###############################################################
#  Generated by:      Cadence Innovus 23.14-s088_1
#  OS:                Linux x86_64(Host ID user1-EliteMini)
#  Generated on:      Sun Jul 19 00:55:51 2026
#  Design:            Multiplier32
#  Command:           write_lef_abstract -noCutObs .outputs/Multiplier.lef
###############################################################

VERSION 5.8 ;

BUSBITCHARS "[]" ;
DIVIDERCHAR "/" ;

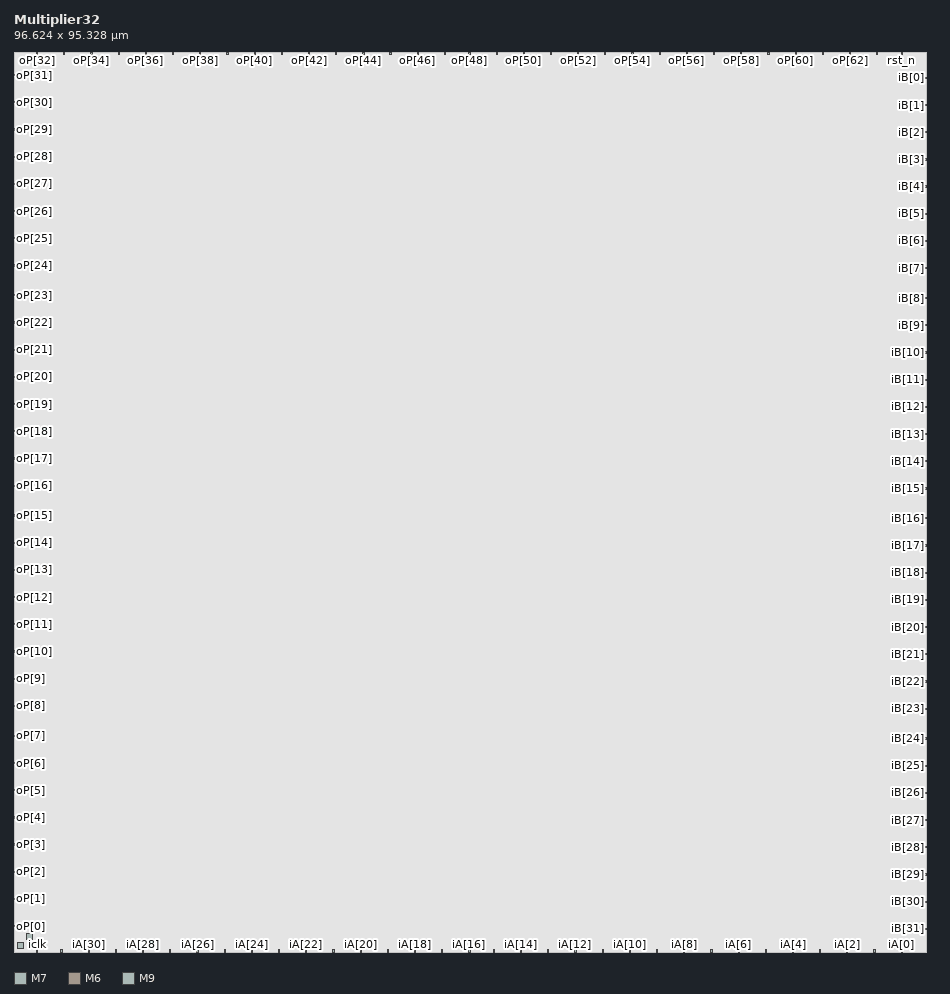
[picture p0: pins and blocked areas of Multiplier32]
MACRO Multiplier32
  CLASS BLOCK ;
  SIZE 96.624000 BY 95.328000 ;
  FOREIGN Multiplier32 0.000000 0.000000 ;
  ORIGIN 0 0 ;
  SYMMETRY X Y R90 ;
  PIN iclk
    DIRECTION INPUT ;
    USE SIGNAL ;
    PORT
      LAYER M7 ;
        RECT 2.384000 0.000000 2.512000 0.288000 ;
    END
  END iclk
  PIN rst_n
    DIRECTION INPUT ;
    USE SIGNAL ;
    PORT
      LAYER M7 ;
        RECT 93.968000 95.040000 94.096000 95.328000 ;
    END
  END rst_n
  PIN iA[31]
    DIRECTION INPUT ;
    USE SIGNAL ;
    PORT
      LAYER M7 ;
        RECT 4.976000 0.000000 5.104000 0.288000 ;
    END
  END iA[31]
  PIN iA[30]
    DIRECTION INPUT ;
    USE SIGNAL ;
    PORT
      LAYER M7 ;
        RECT 7.856000 0.000000 7.984000 0.288000 ;
    END
  END iA[30]
  PIN iA[29]
    DIRECTION INPUT ;
    USE SIGNAL ;
    PORT
      LAYER M7 ;
        RECT 10.736000 0.000000 10.864000 0.288000 ;
    END
  END iA[29]
  PIN iA[28]
    DIRECTION INPUT ;
    USE SIGNAL ;
    PORT
      LAYER M7 ;
        RECT 13.616000 0.000000 13.744000 0.288000 ;
    END
  END iA[28]
  PIN iA[27]
    DIRECTION INPUT ;
    USE SIGNAL ;
    PORT
      LAYER M7 ;
        RECT 16.496000 0.000000 16.624000 0.288000 ;
    END
  END iA[27]
  PIN iA[26]
    DIRECTION INPUT ;
    USE SIGNAL ;
    PORT
      LAYER M7 ;
        RECT 19.376000 0.000000 19.504000 0.288000 ;
    END
  END iA[26]
  PIN iA[25]
    DIRECTION INPUT ;
    USE SIGNAL ;
    PORT
      LAYER M7 ;
        RECT 22.256000 0.000000 22.384000 0.288000 ;
    END
  END iA[25]
  PIN iA[24]
    DIRECTION INPUT ;
    USE SIGNAL ;
    PORT
      LAYER M7 ;
        RECT 25.136000 0.000000 25.264000 0.288000 ;
    END
  END iA[24]
  PIN iA[23]
    DIRECTION INPUT ;
    USE SIGNAL ;
    PORT
      LAYER M7 ;
        RECT 28.016000 0.000000 28.144000 0.288000 ;
    END
  END iA[23]
  PIN iA[22]
    DIRECTION INPUT ;
    USE SIGNAL ;
    PORT
      LAYER M7 ;
        RECT 30.896000 0.000000 31.024000 0.288000 ;
    END
  END iA[22]
  PIN iA[21]
    DIRECTION INPUT ;
    USE SIGNAL ;
    PORT
      LAYER M7 ;
        RECT 33.776000 0.000000 33.904000 0.288000 ;
    END
  END iA[21]
  PIN iA[20]
    DIRECTION INPUT ;
    USE SIGNAL ;
    PORT
      LAYER M7 ;
        RECT 36.656000 0.000000 36.784000 0.288000 ;
    END
  END iA[20]
  PIN iA[19]
    DIRECTION INPUT ;
    USE SIGNAL ;
    PORT
      LAYER M7 ;
        RECT 39.536000 0.000000 39.664000 0.288000 ;
    END
  END iA[19]
  PIN iA[18]
    DIRECTION INPUT ;
    USE SIGNAL ;
    PORT
      LAYER M7 ;
        RECT 42.416000 0.000000 42.544000 0.288000 ;
    END
  END iA[18]
  PIN iA[17]
    DIRECTION INPUT ;
    USE SIGNAL ;
    PORT
      LAYER M7 ;
        RECT 45.296000 0.000000 45.424000 0.288000 ;
    END
  END iA[17]
  PIN iA[16]
    DIRECTION INPUT ;
    USE SIGNAL ;
    PORT
      LAYER M7 ;
        RECT 48.176000 0.000000 48.304000 0.288000 ;
    END
  END iA[16]
  PIN iA[15]
    DIRECTION INPUT ;
    USE SIGNAL ;
    PORT
      LAYER M7 ;
        RECT 50.768000 0.000000 50.896000 0.288000 ;
    END
  END iA[15]
  PIN iA[14]
    DIRECTION INPUT ;
    USE SIGNAL ;
    PORT
      LAYER M7 ;
        RECT 53.648000 0.000000 53.776000 0.288000 ;
    END
  END iA[14]
  PIN iA[13]
    DIRECTION INPUT ;
    USE SIGNAL ;
    PORT
      LAYER M7 ;
        RECT 56.528000 0.000000 56.656000 0.288000 ;
    END
  END iA[13]
  PIN iA[12]
    DIRECTION INPUT ;
    USE SIGNAL ;
    PORT
      LAYER M7 ;
        RECT 59.408000 0.000000 59.536000 0.288000 ;
    END
  END iA[12]
  PIN iA[11]
    DIRECTION INPUT ;
    USE SIGNAL ;
    PORT
      LAYER M7 ;
        RECT 62.288000 0.000000 62.416000 0.288000 ;
    END
  END iA[11]
  PIN iA[10]
    DIRECTION INPUT ;
    USE SIGNAL ;
    PORT
      LAYER M7 ;
        RECT 65.168000 0.000000 65.296000 0.288000 ;
    END
  END iA[10]
  PIN iA[9]
    DIRECTION INPUT ;
    USE SIGNAL ;
    PORT
      LAYER M7 ;
        RECT 68.048000 0.000000 68.176000 0.288000 ;
    END
  END iA[9]
  PIN iA[8]
    DIRECTION INPUT ;
    USE SIGNAL ;
    PORT
      LAYER M7 ;
        RECT 70.928000 0.000000 71.056000 0.288000 ;
    END
  END iA[8]
  PIN iA[7]
    DIRECTION INPUT ;
    USE SIGNAL ;
    PORT
      LAYER M7 ;
        RECT 73.808000 0.000000 73.936000 0.288000 ;
    END
  END iA[7]
  PIN iA[6]
    DIRECTION INPUT ;
    USE SIGNAL ;
    PORT
      LAYER M7 ;
        RECT 76.688000 0.000000 76.816000 0.288000 ;
    END
  END iA[6]
  PIN iA[5]
    DIRECTION INPUT ;
    USE SIGNAL ;
    PORT
      LAYER M7 ;
        RECT 79.568000 0.000000 79.696000 0.288000 ;
    END
  END iA[5]
  PIN iA[4]
    DIRECTION INPUT ;
    USE SIGNAL ;
    PORT
      LAYER M7 ;
        RECT 82.448000 0.000000 82.576000 0.288000 ;
    END
  END iA[4]
  PIN iA[3]
    DIRECTION INPUT ;
    USE SIGNAL ;
    PORT
      LAYER M7 ;
        RECT 85.328000 0.000000 85.456000 0.288000 ;
    END
  END iA[3]
  PIN iA[2]
    DIRECTION INPUT ;
    USE SIGNAL ;
    PORT
      LAYER M7 ;
        RECT 88.208000 0.000000 88.336000 0.288000 ;
    END
  END iA[2]
  PIN iA[1]
    DIRECTION INPUT ;
    USE SIGNAL ;
    PORT
      LAYER M7 ;
        RECT 91.088000 0.000000 91.216000 0.288000 ;
    END
  END iA[1]
  PIN iA[0]
    DIRECTION INPUT ;
    USE SIGNAL ;
    PORT
      LAYER M7 ;
        RECT 93.968000 0.000000 94.096000 0.288000 ;
    END
  END iA[0]
  PIN iB[31]
    DIRECTION INPUT ;
    USE SIGNAL ;
    PORT
      LAYER M6 ;
        RECT 96.336000 2.384000 96.624000 2.512000 ;
    END
  END iB[31]
  PIN iB[30]
    DIRECTION INPUT ;
    USE SIGNAL ;
    PORT
      LAYER M6 ;
        RECT 96.336000 5.264000 96.624000 5.392000 ;
    END
  END iB[30]
  PIN iB[29]
    DIRECTION INPUT ;
    USE SIGNAL ;
    PORT
      LAYER M6 ;
        RECT 96.336000 8.144000 96.624000 8.272000 ;
    END
  END iB[29]
  PIN iB[28]
    DIRECTION INPUT ;
    USE SIGNAL ;
    PORT
      LAYER M6 ;
        RECT 96.336000 11.024000 96.624000 11.152000 ;
    END
  END iB[28]
  PIN iB[27]
    DIRECTION INPUT ;
    USE SIGNAL ;
    PORT
      LAYER M6 ;
        RECT 96.336000 13.904000 96.624000 14.032000 ;
    END
  END iB[27]
  PIN iB[26]
    DIRECTION INPUT ;
    USE SIGNAL ;
    PORT
      LAYER M6 ;
        RECT 96.336000 16.784000 96.624000 16.912000 ;
    END
  END iB[26]
  PIN iB[25]
    DIRECTION INPUT ;
    USE SIGNAL ;
    PORT
      LAYER M6 ;
        RECT 96.336000 19.664000 96.624000 19.792000 ;
    END
  END iB[25]
  PIN iB[24]
    DIRECTION INPUT ;
    USE SIGNAL ;
    PORT
      LAYER M6 ;
        RECT 96.336000 22.544000 96.624000 22.672000 ;
    END
  END iB[24]
  PIN iB[23]
    DIRECTION INPUT ;
    USE SIGNAL ;
    PORT
      LAYER M6 ;
        RECT 96.336000 25.712000 96.624000 25.840000 ;
    END
  END iB[23]
  PIN iB[22]
    DIRECTION INPUT ;
    USE SIGNAL ;
    PORT
      LAYER M6 ;
        RECT 96.336000 28.592000 96.624000 28.720000 ;
    END
  END iB[22]
  PIN iB[21]
    DIRECTION INPUT ;
    USE SIGNAL ;
    PORT
      LAYER M6 ;
        RECT 96.336000 31.472000 96.624000 31.600000 ;
    END
  END iB[21]
  PIN iB[20]
    DIRECTION INPUT ;
    USE SIGNAL ;
    PORT
      LAYER M6 ;
        RECT 96.336000 34.352000 96.624000 34.480000 ;
    END
  END iB[20]
  PIN iB[19]
    DIRECTION INPUT ;
    USE SIGNAL ;
    PORT
      LAYER M6 ;
        RECT 96.336000 37.232000 96.624000 37.360000 ;
    END
  END iB[19]
  PIN iB[18]
    DIRECTION INPUT ;
    USE SIGNAL ;
    PORT
      LAYER M6 ;
        RECT 96.336000 40.112000 96.624000 40.240000 ;
    END
  END iB[18]
  PIN iB[17]
    DIRECTION INPUT ;
    USE SIGNAL ;
    PORT
      LAYER M6 ;
        RECT 96.336000 42.992000 96.624000 43.120000 ;
    END
  END iB[17]
  PIN iB[16]
    DIRECTION INPUT ;
    USE SIGNAL ;
    PORT
      LAYER M6 ;
        RECT 96.336000 45.872000 96.624000 46.000000 ;
    END
  END iB[16]
  PIN iB[15]
    DIRECTION INPUT ;
    USE SIGNAL ;
    PORT
      LAYER M6 ;
        RECT 96.336000 49.040000 96.624000 49.168000 ;
    END
  END iB[15]
  PIN iB[14]
    DIRECTION INPUT ;
    USE SIGNAL ;
    PORT
      LAYER M6 ;
        RECT 96.336000 51.920000 96.624000 52.048000 ;
    END
  END iB[14]
  PIN iB[13]
    DIRECTION INPUT ;
    USE SIGNAL ;
    PORT
      LAYER M6 ;
        RECT 96.336000 54.800000 96.624000 54.928000 ;
    END
  END iB[13]
  PIN iB[12]
    DIRECTION INPUT ;
    USE SIGNAL ;
    PORT
      LAYER M6 ;
        RECT 96.336000 57.680000 96.624000 57.808000 ;
    END
  END iB[12]
  PIN iB[11]
    DIRECTION INPUT ;
    USE SIGNAL ;
    PORT
      LAYER M6 ;
        RECT 96.336000 60.560000 96.624000 60.688000 ;
    END
  END iB[11]
  PIN iB[10]
    DIRECTION INPUT ;
    USE SIGNAL ;
    PORT
      LAYER M6 ;
        RECT 96.336000 63.440000 96.624000 63.568000 ;
    END
  END iB[10]
  PIN iB[9]
    DIRECTION INPUT ;
    USE SIGNAL ;
    PORT
      LAYER M6 ;
        RECT 96.336000 66.320000 96.624000 66.448000 ;
    END
  END iB[9]
  PIN iB[8]
    DIRECTION INPUT ;
    USE SIGNAL ;
    PORT
      LAYER M6 ;
        RECT 96.336000 69.200000 96.624000 69.328000 ;
    END
  END iB[8]
  PIN iB[7]
    DIRECTION INPUT ;
    USE SIGNAL ;
    PORT
      LAYER M6 ;
        RECT 96.336000 72.368000 96.624000 72.496000 ;
    END
  END iB[7]
  PIN iB[6]
    DIRECTION INPUT ;
    USE SIGNAL ;
    PORT
      LAYER M6 ;
        RECT 96.336000 75.248000 96.624000 75.376000 ;
    END
  END iB[6]
  PIN iB[5]
    DIRECTION INPUT ;
    USE SIGNAL ;
    PORT
      LAYER M6 ;
        RECT 96.336000 78.128000 96.624000 78.256000 ;
    END
  END iB[5]
  PIN iB[4]
    DIRECTION INPUT ;
    USE SIGNAL ;
    PORT
      LAYER M6 ;
        RECT 96.336000 81.008000 96.624000 81.136000 ;
    END
  END iB[4]
  PIN iB[3]
    DIRECTION INPUT ;
    USE SIGNAL ;
    PORT
      LAYER M6 ;
        RECT 96.336000 83.888000 96.624000 84.016000 ;
    END
  END iB[3]
  PIN iB[2]
    DIRECTION INPUT ;
    USE SIGNAL ;
    PORT
      LAYER M6 ;
        RECT 96.336000 86.768000 96.624000 86.896000 ;
    END
  END iB[2]
  PIN iB[1]
    DIRECTION INPUT ;
    USE SIGNAL ;
    PORT
      LAYER M6 ;
        RECT 96.336000 89.648000 96.624000 89.776000 ;
    END
  END iB[1]
  PIN iB[0]
    DIRECTION INPUT ;
    USE SIGNAL ;
    PORT
      LAYER M6 ;
        RECT 96.336000 92.528000 96.624000 92.656000 ;
    END
  END iB[0]
  PIN oP[63]
    DIRECTION OUTPUT ;
    USE SIGNAL ;
    PORT
      LAYER M7 ;
        RECT 91.376000 95.040000 91.504000 95.328000 ;
    END
  END oP[63]
  PIN oP[62]
    DIRECTION OUTPUT ;
    USE SIGNAL ;
    PORT
      LAYER M7 ;
        RECT 88.496000 95.040000 88.624000 95.328000 ;
    END
  END oP[62]
  PIN oP[61]
    DIRECTION OUTPUT ;
    USE SIGNAL ;
    PORT
      LAYER M7 ;
        RECT 85.616000 95.040000 85.744000 95.328000 ;
    END
  END oP[61]
  PIN oP[60]
    DIRECTION OUTPUT ;
    USE SIGNAL ;
    PORT
      LAYER M7 ;
        RECT 82.736000 95.040000 82.864000 95.328000 ;
    END
  END oP[60]
  PIN oP[59]
    DIRECTION OUTPUT ;
    USE SIGNAL ;
    PORT
      LAYER M7 ;
        RECT 79.856000 95.040000 79.984000 95.328000 ;
    END
  END oP[59]
  PIN oP[58]
    DIRECTION OUTPUT ;
    USE SIGNAL ;
    PORT
      LAYER M7 ;
        RECT 76.976000 95.040000 77.104000 95.328000 ;
    END
  END oP[58]
  PIN oP[57]
    DIRECTION OUTPUT ;
    USE SIGNAL ;
    PORT
      LAYER M7 ;
        RECT 74.096000 95.040000 74.224000 95.328000 ;
    END
  END oP[57]
  PIN oP[56]
    DIRECTION OUTPUT ;
    USE SIGNAL ;
    PORT
      LAYER M7 ;
        RECT 71.216000 95.040000 71.344000 95.328000 ;
    END
  END oP[56]
  PIN oP[55]
    DIRECTION OUTPUT ;
    USE SIGNAL ;
    PORT
      LAYER M7 ;
        RECT 68.336000 95.040000 68.464000 95.328000 ;
    END
  END oP[55]
  PIN oP[54]
    DIRECTION OUTPUT ;
    USE SIGNAL ;
    PORT
      LAYER M7 ;
        RECT 65.456000 95.040000 65.584000 95.328000 ;
    END
  END oP[54]
  PIN oP[53]
    DIRECTION OUTPUT ;
    USE SIGNAL ;
    PORT
      LAYER M7 ;
        RECT 62.576000 95.040000 62.704000 95.328000 ;
    END
  END oP[53]
  PIN oP[52]
    DIRECTION OUTPUT ;
    USE SIGNAL ;
    PORT
      LAYER M7 ;
        RECT 59.696000 95.040000 59.824000 95.328000 ;
    END
  END oP[52]
  PIN oP[51]
    DIRECTION OUTPUT ;
    USE SIGNAL ;
    PORT
      LAYER M7 ;
        RECT 56.816000 95.040000 56.944000 95.328000 ;
    END
  END oP[51]
  PIN oP[50]
    DIRECTION OUTPUT ;
    USE SIGNAL ;
    PORT
      LAYER M7 ;
        RECT 53.936000 95.040000 54.064000 95.328000 ;
    END
  END oP[50]
  PIN oP[49]
    DIRECTION OUTPUT ;
    USE SIGNAL ;
    PORT
      LAYER M7 ;
        RECT 51.056000 95.040000 51.184000 95.328000 ;
    END
  END oP[49]
  PIN oP[48]
    DIRECTION OUTPUT ;
    USE SIGNAL ;
    PORT
      LAYER M7 ;
        RECT 48.176000 95.040000 48.304000 95.328000 ;
    END
  END oP[48]
  PIN oP[47]
    DIRECTION OUTPUT ;
    USE SIGNAL ;
    PORT
      LAYER M7 ;
        RECT 45.584000 95.040000 45.712000 95.328000 ;
    END
  END oP[47]
  PIN oP[46]
    DIRECTION OUTPUT ;
    USE SIGNAL ;
    PORT
      LAYER M7 ;
        RECT 42.704000 95.040000 42.832000 95.328000 ;
    END
  END oP[46]
  PIN oP[45]
    DIRECTION OUTPUT ;
    USE SIGNAL ;
    PORT
      LAYER M7 ;
        RECT 39.824000 95.040000 39.952000 95.328000 ;
    END
  END oP[45]
  PIN oP[44]
    DIRECTION OUTPUT ;
    USE SIGNAL ;
    PORT
      LAYER M7 ;
        RECT 36.944000 95.040000 37.072000 95.328000 ;
    END
  END oP[44]
  PIN oP[43]
    DIRECTION OUTPUT ;
    USE SIGNAL ;
    PORT
      LAYER M7 ;
        RECT 34.064000 95.040000 34.192000 95.328000 ;
    END
  END oP[43]
  PIN oP[42]
    DIRECTION OUTPUT ;
    USE SIGNAL ;
    PORT
      LAYER M7 ;
        RECT 31.184000 95.040000 31.312000 95.328000 ;
    END
  END oP[42]
  PIN oP[41]
    DIRECTION OUTPUT ;
    USE SIGNAL ;
    PORT
      LAYER M7 ;
        RECT 28.304000 95.040000 28.432000 95.328000 ;
    END
  END oP[41]
  PIN oP[40]
    DIRECTION OUTPUT ;
    USE SIGNAL ;
    PORT
      LAYER M7 ;
        RECT 25.424000 95.040000 25.552000 95.328000 ;
    END
  END oP[40]
  PIN oP[39]
    DIRECTION OUTPUT ;
    USE SIGNAL ;
    PORT
      LAYER M7 ;
        RECT 22.544000 95.040000 22.672000 95.328000 ;
    END
  END oP[39]
  PIN oP[38]
    DIRECTION OUTPUT ;
    USE SIGNAL ;
    PORT
      LAYER M7 ;
        RECT 19.664000 95.040000 19.792000 95.328000 ;
    END
  END oP[38]
  PIN oP[37]
    DIRECTION OUTPUT ;
    USE SIGNAL ;
    PORT
      LAYER M7 ;
        RECT 16.784000 95.040000 16.912000 95.328000 ;
    END
  END oP[37]
  PIN oP[36]
    DIRECTION OUTPUT ;
    USE SIGNAL ;
    PORT
      LAYER M7 ;
        RECT 13.904000 95.040000 14.032000 95.328000 ;
    END
  END oP[36]
  PIN oP[35]
    DIRECTION OUTPUT ;
    USE SIGNAL ;
    PORT
      LAYER M7 ;
        RECT 11.024000 95.040000 11.152000 95.328000 ;
    END
  END oP[35]
  PIN oP[34]
    DIRECTION OUTPUT ;
    USE SIGNAL ;
    PORT
      LAYER M7 ;
        RECT 8.144000 95.040000 8.272000 95.328000 ;
    END
  END oP[34]
  PIN oP[33]
    DIRECTION OUTPUT ;
    USE SIGNAL ;
    PORT
      LAYER M7 ;
        RECT 5.264000 95.040000 5.392000 95.328000 ;
    END
  END oP[33]
  PIN oP[32]
    DIRECTION OUTPUT ;
    USE SIGNAL ;
    PORT
      LAYER M7 ;
        RECT 2.384000 95.040000 2.512000 95.328000 ;
    END
  END oP[32]
  PIN oP[31]
    DIRECTION OUTPUT ;
    USE SIGNAL ;
    PORT
      LAYER M6 ;
        RECT 0.000000 92.816000 0.288000 92.944000 ;
    END
  END oP[31]
  PIN oP[30]
    DIRECTION OUTPUT ;
    USE SIGNAL ;
    PORT
      LAYER M6 ;
        RECT 0.000000 89.936000 0.288000 90.064000 ;
    END
  END oP[30]
  PIN oP[29]
    DIRECTION OUTPUT ;
    USE SIGNAL ;
    PORT
      LAYER M6 ;
        RECT 0.000000 87.056000 0.288000 87.184000 ;
    END
  END oP[29]
  PIN oP[28]
    DIRECTION OUTPUT ;
    USE SIGNAL ;
    PORT
      LAYER M6 ;
        RECT 0.000000 84.176000 0.288000 84.304000 ;
    END
  END oP[28]
  PIN oP[27]
    DIRECTION OUTPUT ;
    USE SIGNAL ;
    PORT
      LAYER M6 ;
        RECT 0.000000 81.296000 0.288000 81.424000 ;
    END
  END oP[27]
  PIN oP[26]
    DIRECTION OUTPUT ;
    USE SIGNAL ;
    PORT
      LAYER M6 ;
        RECT 0.000000 78.416000 0.288000 78.544000 ;
    END
  END oP[26]
  PIN oP[25]
    DIRECTION OUTPUT ;
    USE SIGNAL ;
    PORT
      LAYER M6 ;
        RECT 0.000000 75.536000 0.288000 75.664000 ;
    END
  END oP[25]
  PIN oP[24]
    DIRECTION OUTPUT ;
    USE SIGNAL ;
    PORT
      LAYER M6 ;
        RECT 0.000000 72.656000 0.288000 72.784000 ;
    END
  END oP[24]
  PIN oP[23]
    DIRECTION OUTPUT ;
    USE SIGNAL ;
    PORT
      LAYER M6 ;
        RECT 0.000000 69.488000 0.288000 69.616000 ;
    END
  END oP[23]
  PIN oP[22]
    DIRECTION OUTPUT ;
    USE SIGNAL ;
    PORT
      LAYER M6 ;
        RECT 0.000000 66.608000 0.288000 66.736000 ;
    END
  END oP[22]
  PIN oP[21]
    DIRECTION OUTPUT ;
    USE SIGNAL ;
    PORT
      LAYER M6 ;
        RECT 0.000000 63.728000 0.288000 63.856000 ;
    END
  END oP[21]
  PIN oP[20]
    DIRECTION OUTPUT ;
    USE SIGNAL ;
    PORT
      LAYER M6 ;
        RECT 0.000000 60.848000 0.288000 60.976000 ;
    END
  END oP[20]
  PIN oP[19]
    DIRECTION OUTPUT ;
    USE SIGNAL ;
    PORT
      LAYER M6 ;
        RECT 0.000000 57.968000 0.288000 58.096000 ;
    END
  END oP[19]
  PIN oP[18]
    DIRECTION OUTPUT ;
    USE SIGNAL ;
    PORT
      LAYER M6 ;
        RECT 0.000000 55.088000 0.288000 55.216000 ;
    END
  END oP[18]
  PIN oP[17]
    DIRECTION OUTPUT ;
    USE SIGNAL ;
    PORT
      LAYER M6 ;
        RECT 0.000000 52.208000 0.288000 52.336000 ;
    END
  END oP[17]
  PIN oP[16]
    DIRECTION OUTPUT ;
    USE SIGNAL ;
    PORT
      LAYER M6 ;
        RECT 0.000000 49.328000 0.288000 49.456000 ;
    END
  END oP[16]
  PIN oP[15]
    DIRECTION OUTPUT ;
    USE SIGNAL ;
    PORT
      LAYER M6 ;
        RECT 0.000000 46.160000 0.288000 46.288000 ;
    END
  END oP[15]
  PIN oP[14]
    DIRECTION OUTPUT ;
    USE SIGNAL ;
    PORT
      LAYER M6 ;
        RECT 0.000000 43.280000 0.288000 43.408000 ;
    END
  END oP[14]
  PIN oP[13]
    DIRECTION OUTPUT ;
    USE SIGNAL ;
    PORT
      LAYER M6 ;
        RECT 0.000000 40.400000 0.288000 40.528000 ;
    END
  END oP[13]
  PIN oP[12]
    DIRECTION OUTPUT ;
    USE SIGNAL ;
    PORT
      LAYER M6 ;
        RECT 0.000000 37.520000 0.288000 37.648000 ;
    END
  END oP[12]
  PIN oP[11]
    DIRECTION OUTPUT ;
    USE SIGNAL ;
    PORT
      LAYER M6 ;
        RECT 0.000000 34.640000 0.288000 34.768000 ;
    END
  END oP[11]
  PIN oP[10]
    DIRECTION OUTPUT ;
    USE SIGNAL ;
    PORT
      LAYER M6 ;
        RECT 0.000000 31.760000 0.288000 31.888000 ;
    END
  END oP[10]
  PIN oP[9]
    DIRECTION OUTPUT ;
    USE SIGNAL ;
    PORT
      LAYER M6 ;
        RECT 0.000000 28.880000 0.288000 29.008000 ;
    END
  END oP[9]
  PIN oP[8]
    DIRECTION OUTPUT ;
    USE SIGNAL ;
    PORT
      LAYER M6 ;
        RECT 0.000000 26.000000 0.288000 26.128000 ;
    END
  END oP[8]
  PIN oP[7]
    DIRECTION OUTPUT ;
    USE SIGNAL ;
    PORT
      LAYER M6 ;
        RECT 0.000000 22.832000 0.288000 22.960000 ;
    END
  END oP[7]
  PIN oP[6]
    DIRECTION OUTPUT ;
    USE SIGNAL ;
    PORT
      LAYER M6 ;
        RECT 0.000000 19.952000 0.288000 20.080000 ;
    END
  END oP[6]
  PIN oP[5]
    DIRECTION OUTPUT ;
    USE SIGNAL ;
    PORT
      LAYER M6 ;
        RECT 0.000000 17.072000 0.288000 17.200000 ;
    END
  END oP[5]
  PIN oP[4]
    DIRECTION OUTPUT ;
    USE SIGNAL ;
    PORT
      LAYER M6 ;
        RECT 0.000000 14.192000 0.288000 14.320000 ;
    END
  END oP[4]
  PIN oP[3]
    DIRECTION OUTPUT ;
    USE SIGNAL ;
    PORT
      LAYER M6 ;
        RECT 0.000000 11.312000 0.288000 11.440000 ;
    END
  END oP[3]
  PIN oP[2]
    DIRECTION OUTPUT ;
    USE SIGNAL ;
    PORT
      LAYER M6 ;
        RECT 0.000000 8.432000 0.288000 8.560000 ;
    END
  END oP[2]
  PIN oP[1]
    DIRECTION OUTPUT ;
    USE SIGNAL ;
    PORT
      LAYER M6 ;
        RECT 0.000000 5.552000 0.288000 5.680000 ;
    END
  END oP[1]
  PIN oP[0]
    DIRECTION OUTPUT ;
    USE SIGNAL ;
    PORT
      LAYER M6 ;
        RECT 0.000000 2.672000 0.288000 2.800000 ;
    END
  END oP[0]
  PIN VDD
    DIRECTION INOUT ;
    USE POWER ;
    PORT
      LAYER M9 ;
        RECT 1.344000 1.344000 1.984000 1.984000 ;
    END
  END VDD
  PIN VSS
    DIRECTION INOUT ;
    USE GROUND ;
    PORT
      LAYER M9 ;
        RECT 0.384000 0.384000 1.024000 1.024000 ;
    END
  END VSS
  OBS
    LAYER M1 ;
      RECT 0.000000 0.000000 96.624000 95.328000 ;
    LAYER M2 ;
      RECT 0.000000 0.000000 96.624000 95.328000 ;
    LAYER M3 ;
      RECT 0.000000 0.000000 96.624000 95.328000 ;
    LAYER M4 ;
      RECT 0.000000 0.000000 96.624000 95.328000 ;
    LAYER M5 ;
      RECT 0.000000 0.000000 96.624000 95.328000 ;
    LAYER M6 ;
      RECT 0.000000 0.000000 96.624000 95.328000 ;
    LAYER M7 ;
      RECT 0.000000 0.000000 96.624000 95.328000 ;
    LAYER M8 ;
      RECT 0.000000 0.000000 96.624000 95.328000 ;
    LAYER M9 ;
      RECT 0.000000 0.000000 96.624000 95.328000 ;
    LAYER Pad ;
      RECT 0.000000 0.000000 96.624000 95.328000 ;
  END
END Multiplier32

END LIBRARY
